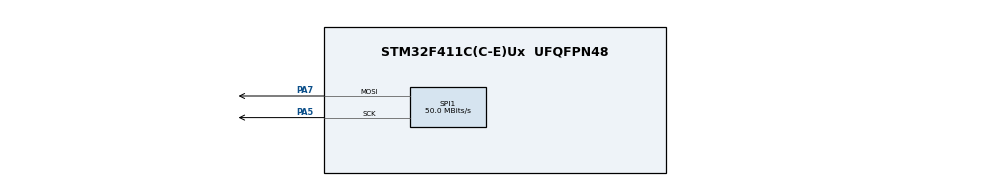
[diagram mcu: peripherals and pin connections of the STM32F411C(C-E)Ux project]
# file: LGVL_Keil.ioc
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Dma.Request0=SPI1_TX
Dma.SPI1_TX.0.Direction=DMA_MEMORY_TO_PERIPH
Dma.SPI1_TX.0.FIFOMode=DMA_FIFOMODE_DISABLE
Dma.SPI1_TX.0.Instance=DMA2_Stream2
Dma.SPI1_TX.0.MemDataAlignment=DMA_MDATAALIGN_BYTE
Dma.SPI1_TX.0.MemInc=DMA_MINC_ENABLE
Dma.SPI1_TX.0.Mode=DMA_NORMAL
Dma.SPI1_TX.0.PeriphDataAlignment=DMA_PDATAALIGN_BYTE
Dma.SPI1_TX.0.PeriphInc=DMA_PINC_DISABLE
Dma.SPI1_TX.0.Priority=DMA_PRIORITY_LOW
Mcu.Family=STM32F4
Mcu.Name=STM32F411C(C-E)Ux
Mcu.Package=UFQFPN48
NVIC.DMA2_Stream2_IRQn=true\:0\:0\:false\:false\:true\:false\:true\:true
NVIC.PriorityGroup=NVIC_PRIORITYGROUP_4
PA5.Mode=TX_Only_Simplex_Unidirect_Master
PA5.Signal=SPI1_SCK
PA7.Mode=TX_Only_Simplex_Unidirect_Master
PA7.Signal=SPI1_MOSI
PH0\ -\ OSC_IN.Mode=HSE-External-Oscillator
PH0\ -\ OSC_IN.Signal=RCC_OSC_IN
PH1\ -\ OSC_OUT.Mode=HSE-External-Oscillator
PH1\ -\ OSC_OUT.Signal=RCC_OSC_OUT
ProjectManager.HeapSize=0x200
ProjectManager.StackSize=0x800
ProjectManager.TargetToolchain=MDK-ARM V5.32
RCC.48MHZClocksFreq_Value=50000000
RCC.AHBFreq_Value=100000000
RCC.APB1CLKDivider=RCC_HCLK_DIV2
RCC.APB1Freq_Value=50000000
RCC.APB1TimFreq_Value=100000000
RCC.APB2Freq_Value=100000000
RCC.APB2TimFreq_Value=100000000
RCC.CortexFreq_Value=100000000
RCC.HCLKFreq_Value=100000000
RCC.HSE_VALUE=25000000
RCC.HSI_VALUE=16000000
RCC.LSE_VALUE=32768
RCC.PLLM=8
RCC.PLLN=100
RCC.SYSCLKFreq_VALUE=100000000
RCC.SYSCLKSource=RCC_SYSCLKSOURCE_PLLCLK
RCC.VCOOutputFreq_Value=200000000
SPI1.CLKPhase=SPI_PHASE_2EDGE
SPI1.CLKPolarity=SPI_POLARITY_HIGH
SPI1.CalculateBaudRate=50.0 MBits/s
SPI1.Direction=SPI_DIRECTION_2LINES
SPI1.Mode=SPI_MODE_MASTER
SPI1.VirtualType=VM_MASTER
board=custom

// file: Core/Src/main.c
/* USER CODE BEGIN Header */
/**
  ******************************************************************************
  * @file           : main.c
  * @brief          : Main program body
  ******************************************************************************
  * @attention
  *
  * Copyright (c) 2023 STMicroelectronics.
  * All rights reserved.
  *
  * This software is licensed under terms that can be found in the LICENSE file
  * in the root directory of this software component.
  * If no LICENSE file comes with this software, it is provided AS-IS.
  *
  ******************************************************************************
  */
/* USER CODE END Header */
#include "main.h"

/* USER CODE BEGIN Includes */
#include "lv_port_disp_template.h"
#include "lvgl.h"
#include "sys.h"
#include "demos/benchmark/lv_demo_benchmark.h"
/* USER CODE END Includes */

SPI_HandleTypeDef hspi1;
DMA_HandleTypeDef hdma_spi1_tx;

void SystemClock_Config(void);
static void MX_GPIO_Init(void);
static void MX_DMA_Init(void);
static void MX_SPI1_Init(void);

int main(void)
{

  /* MCU Configuration--------------------------------------------------------*/

  /* Reset of all peripherals, Initializes the Flash interface and the Systick. */
  HAL_Init();

  /* Configure the system clock */
  // SystemClock_Config();

  /* USER CODE BEGIN SysInit */
	Stm32F411_Clock_Init(144,15,2,5);
  /* USER CODE END SysInit */

  /* Initialize all configured peripherals */
  MX_GPIO_Init();
  MX_DMA_Init();
  MX_SPI1_Init();
  /* USER CODE BEGIN 2 */
	lv_init();
  lv_port_disp_init();
	lv_demo_benchmark(LV_DEMO_BENCHMARK_MODE_REAL);
  /* USER CODE END 2 */

  /* Infinite loop */
  /* USER CODE BEGIN WHILE */
  while (1)
  {
		lv_timer_handler();
		HAL_Delay(5);
    /* USER CODE END WHILE */

  }
}

void SystemClock_Config(void)
{
  RCC_OscInitTypeDef RCC_OscInitStruct = {0};
  RCC_ClkInitTypeDef RCC_ClkInitStruct = {0};

  /** Configure the main internal regulator output voltage
  */
  __HAL_RCC_PWR_CLK_ENABLE();
  __HAL_PWR_VOLTAGESCALING_CONFIG(PWR_REGULATOR_VOLTAGE_SCALE1);

  /** Initializes the RCC Oscillators according to the specified parameters
  * in the RCC_OscInitTypeDef structure.
  */
  RCC_OscInitStruct.OscillatorType = RCC_OSCILLATORTYPE_HSI;
  RCC_OscInitStruct.HSIState = RCC_HSI_ON;
  RCC_OscInitStruct.HSICalibrationValue = RCC_HSICALIBRATION_DEFAULT;
  RCC_OscInitStruct.PLL.PLLState = RCC_PLL_ON;
  RCC_OscInitStruct.PLL.PLLSource = RCC_PLLSOURCE_HSI;
  RCC_OscInitStruct.PLL.PLLM = 8;
  RCC_OscInitStruct.PLL.PLLN = 150;
  RCC_OscInitStruct.PLL.PLLP = RCC_PLLP_DIV2;
  RCC_OscInitStruct.PLL.PLLQ = 4;
  if (HAL_RCC_OscConfig(&RCC_OscInitStruct) != HAL_OK)
  {
    Error_Handler();
  }

  /** Initializes the CPU, AHB and APB buses clocks
  */
  RCC_ClkInitStruct.ClockType = RCC_CLOCKTYPE_HCLK|RCC_CLOCKTYPE_SYSCLK
                              |RCC_CLOCKTYPE_PCLK1|RCC_CLOCKTYPE_PCLK2;
  RCC_ClkInitStruct.SYSCLKSource = RCC_SYSCLKSOURCE_PLLCLK;
  RCC_ClkInitStruct.AHBCLKDivider = RCC_SYSCLK_DIV1;
  RCC_ClkInitStruct.APB1CLKDivider = RCC_HCLK_DIV2;
  RCC_ClkInitStruct.APB2CLKDivider = RCC_HCLK_DIV1;

  if (HAL_RCC_ClockConfig(&RCC_ClkInitStruct, FLASH_LATENCY_3) != HAL_OK)
  {
    Error_Handler();
  }
}

static void MX_SPI1_Init(void)
{

  /* SPI1 parameter configuration*/
  hspi1.Instance = SPI1;
  hspi1.Init.Mode = SPI_MODE_MASTER;
  hspi1.Init.Direction = SPI_DIRECTION_2LINES;
  hspi1.Init.DataSize = SPI_DATASIZE_8BIT;
  hspi1.Init.CLKPolarity = SPI_POLARITY_HIGH;
  hspi1.Init.CLKPhase = SPI_PHASE_2EDGE;
  hspi1.Init.NSS = SPI_NSS_SOFT;
  hspi1.Init.BaudRatePrescaler = SPI_BAUDRATEPRESCALER_2;
  hspi1.Init.FirstBit = SPI_FIRSTBIT_MSB;
  hspi1.Init.TIMode = SPI_TIMODE_DISABLE;
  hspi1.Init.CRCCalculation = SPI_CRCCALCULATION_DISABLE;
  hspi1.Init.CRCPolynomial = 10;
  if (HAL_SPI_Init(&hspi1) != HAL_OK)
  {
    Error_Handler();
  }

}

static void MX_DMA_Init(void)
{

  /* DMA controller clock enable */
  __HAL_RCC_DMA2_CLK_ENABLE();

  /* DMA interrupt init */
  /* DMA2_Stream2_IRQn interrupt configuration */
  HAL_NVIC_SetPriority(DMA2_Stream2_IRQn, 0, 0);
  HAL_NVIC_EnableIRQ(DMA2_Stream2_IRQn);

}

static void MX_GPIO_Init(void)
{

  /* GPIO Ports Clock Enable */
  __HAL_RCC_GPIOH_CLK_ENABLE();
  __HAL_RCC_GPIOA_CLK_ENABLE();

}

void Error_Handler(void)
{
  __disable_irq();
  while (1)
  {
  }
}
